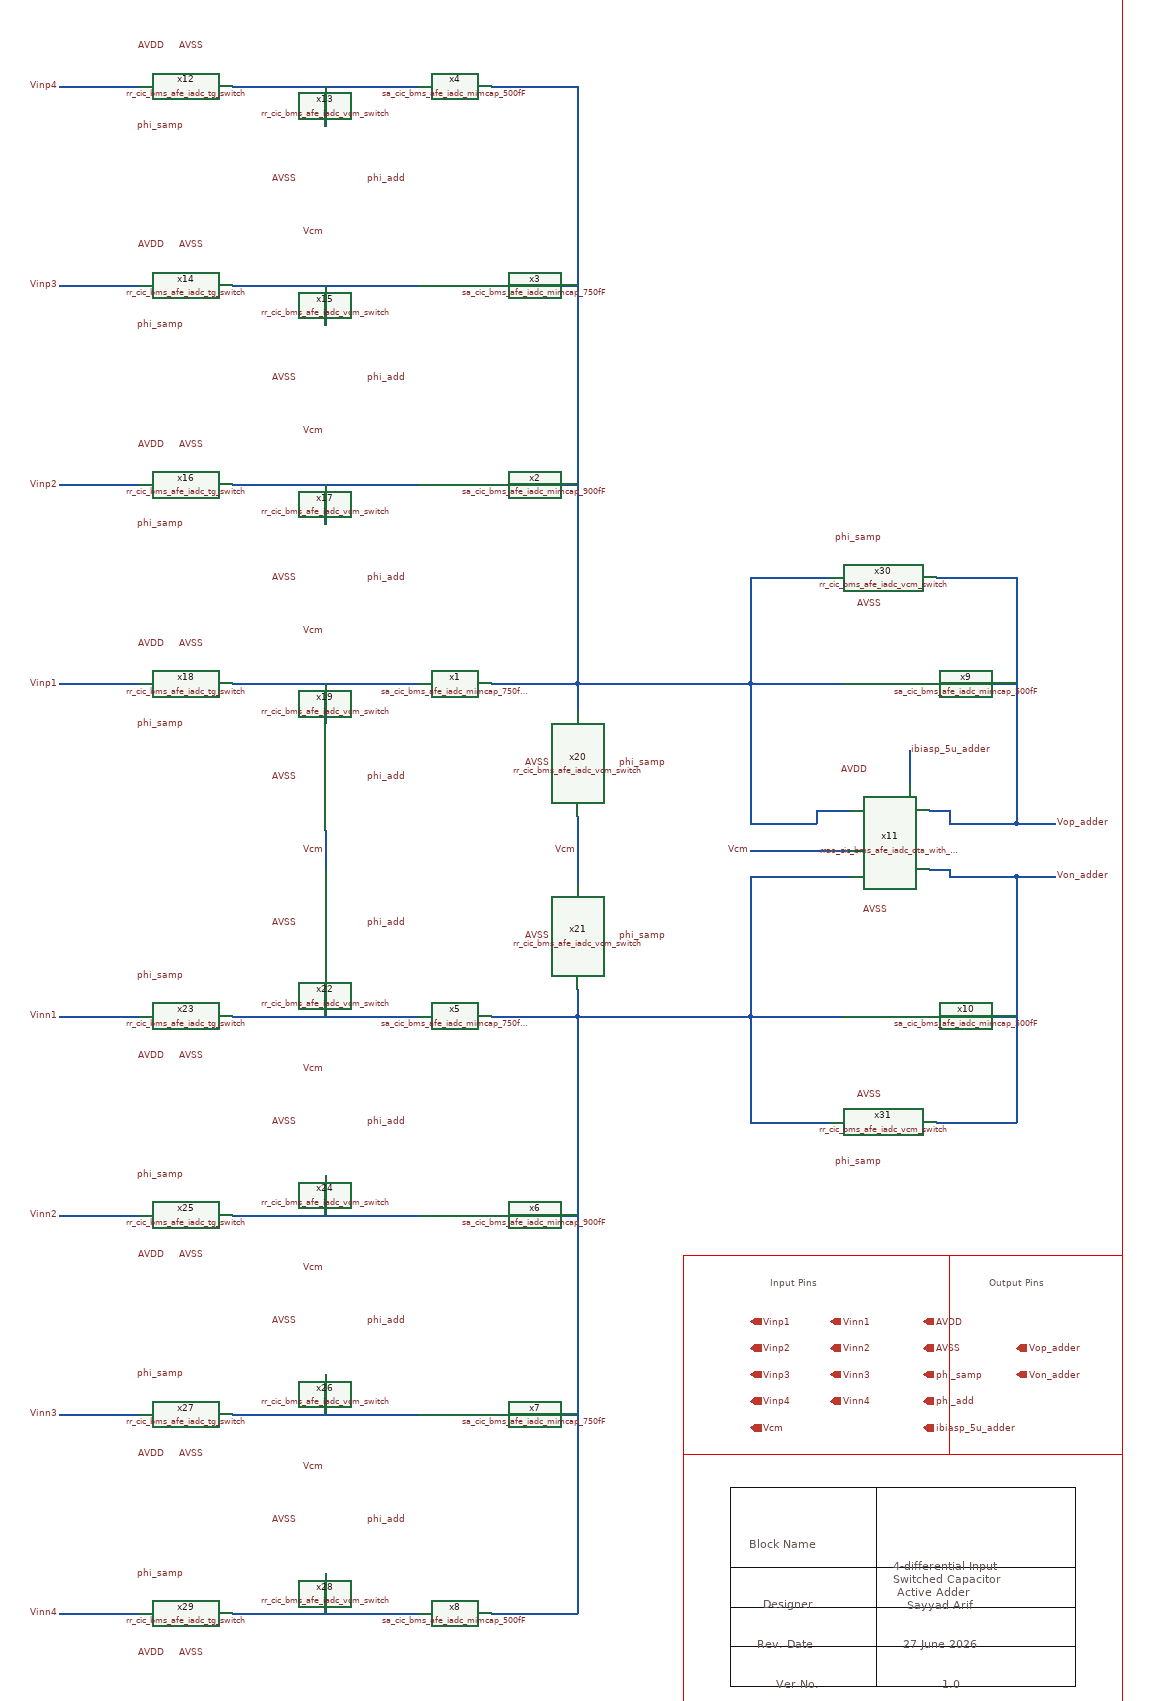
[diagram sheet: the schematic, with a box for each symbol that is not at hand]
v {xschem version=3.4.8RC file_version=1.3}
G {}
K {}
V {}
S {}
F {}
E {}
L 3 1130 -330 1130 -270 {}
L 3 1130 -270 1350 -270 {}
L 3 1350 -330 1350 -270 {}
L 3 1130 -330 1350 -330 {}
L 3 1350 -330 1350 -270 {}
L 3 1350 -270 1650 -270 {}
L 3 1650 -330 1650 -270 {}
L 3 1350 -330 1650 -330 {}
L 3 1130 -270 1130 -210 {}
L 3 1130 -210 1350 -210 {}
L 3 1350 -270 1350 -210 {}
L 3 1350 -270 1350 -210 {}
L 3 1350 -210 1650 -210 {}
L 3 1650 -270 1650 -210 {}
L 3 1130 -210 1130 -150 {}
L 3 1130 -150 1350 -150 {}
L 3 1350 -210 1350 -150 {}
L 3 1350 -210 1350 -150 {}
L 3 1350 -150 1650 -150 {}
L 3 1650 -210 1650 -150 {}
L 3 1130 -450 1130 -330 {}
L 3 1130 -330 1350 -330 {}
L 3 1350 -450 1350 -330 {}
L 3 1130 -450 1350 -450 {}
L 3 1350 -390 1350 -330 {}
L 3 1350 -330 1590 -330 {}
L 3 1650 -450 1650 -330 {}
L 3 1350 -450 1650 -450 {}
L 7 0 -100 1720 -100 {}
L 7 1720 -2720 1720 0 {}
L 7 0 0 1720 0 {}
L 7 0 -2720 0 0 {}
L 7 0 -2720 1720 -2720 {}
L 7 1060 -500 1720 -500 {}
L 7 1060 -800 1060 -500 {}
L 7 1060 -800 1460 -800 {}
L 7 1460 -800 1460 -500 {}
L 7 1460 -800 1720 -800 {}
L 7 1060 -500 1060 -100 {}
T {Input Pins} 1190 -770 0 0 0.4 0.4 {layer=7
weight=bold}
T {Output Pins} 1520 -770 0 0 0.4 0.4 {layer=7
weight=bold}
T {Designer} 1179 -286 2 1 0.5 0.5 {weight=bold layer=3}
T {Sayyad Arif} 1396 -284 2 1 0.5 0.5 {layer=3}
T {Rev. Date} 1170 -226 2 1 0.5 0.5 {weight=bold layer=3}
T {27 June 2026} 1390 -226 2 1 0.5 0.5 {layer=3}
T {Ver No.} 1200 -166 2 1 0.5 0.5 {weight=bold layer=3}
T {1.0} 1450 -166 2 1 0.5 0.5 {layer=3}
T {Block Name} 1159 -376 2 1 0.5 0.5 {weight=bold layer=3}
T {4-differential Input
Switched Capacitor
   Active Adder} 1376 -344 2 1 0.5 0.5 {layer=3}
N 520 -2560 520 -2500 {lab=#net1}
N 380 -2560 530 -2560 {lab=#net1}
N 530 -2560 660 -2560 {lab=#net1}
N 520 -2260 520 -2200 {lab=#net2}
N 520 -1960 520 -1900 {lab=#net3}
N 530 -1960 660 -1960 {lab=#net3}
N 520 -1660 520 -1600 {lab=#net4}
N 530 -1660 660 -1660 {lab=#net4}
N 120 -2560 240 -2560 {lab=Vinp4}
N 380 -2260 530 -2260 {lab=#net2}
N 120 -2260 240 -2260 {lab=Vinp3}
N 380 -1960 530 -1960 {lab=#net3}
N 120 -1960 240 -1960 {lab=Vinp2}
N 380 -1660 530 -1660 {lab=#net4}
N 120 -1660 240 -1660 {lab=Vinp1}
N 530 -2260 660 -2260 {lab=#net2}
N 900 -1660 900 -1620 {lab=#net5}
N 770 -1660 900 -1660 {lab=#net5}
N 900 -1460 900 -1360 {lab=Vcm}
N 520 -1220 520 -1160 {lab=#net6}
N 530 -1160 660 -1160 {lab=#net6}
N 380 -1160 530 -1160 {lab=#net6}
N 120 -1160 240 -1160 {lab=Vinn1}
N 520 -1440 520 -1380 {lab=Vcm}
N 770 -1160 900 -1160 {lab=#net7}
N 900 -1200 900 -1160 {lab=#net7}
N 520 -920 520 -860 {lab=#net8}
N 530 -860 660 -860 {lab=#net8}
N 380 -860 530 -860 {lab=#net8}
N 120 -860 240 -860 {lab=Vinn2}
N 520 -620 520 -560 {lab=#net9}
N 530 -560 660 -560 {lab=#net9}
N 380 -560 530 -560 {lab=#net9}
N 120 -560 240 -560 {lab=Vinn3}
N 520 -320 520 -260 {lab=#net10}
N 530 -260 660 -260 {lab=#net10}
N 380 -260 530 -260 {lab=#net10}
N 120 -260 240 -260 {lab=Vinn4}
N 770 -260 900 -260 {lab=#net7}
N 900 -1160 900 -260 {lab=#net7}
N 770 -860 900 -860 {lab=#net7}
N 770 -560 900 -560 {lab=#net7}
N 770 -1960 900 -1960 {lab=#net5}
N 770 -2260 900 -2260 {lab=#net5}
N 770 -2560 900 -2560 {lab=#net5}
N 900 -2560 900 -1660 {lab=#net5}
N 1400 -1560 1400 -1510 {lab=ibiasp_5u_adder}
N 1160 -1160 1300 -1160 {lab=#net7}
N 1160 -1370 1160 -1160 {lab=#net7}
N 1160 -1370 1260 -1370 {lab=#net7}
N 1160 -1660 1160 -1450 {lab=#net5}
N 1160 -1660 1300 -1660 {lab=#net5}
N 1160 -1820 1280 -1820 {lab=#net5}
N 1160 -1820 1160 -1660 {lab=#net5}
N 900 -1660 1160 -1660 {lab=#net5}
N 1460 -1450 1560 -1450 {lab=Vop_adder}
N 1560 -1820 1560 -1450 {lab=Vop_adder}
N 1440 -1820 1560 -1820 {lab=Vop_adder}
N 1410 -1660 1560 -1660 {lab=Vop_adder}
N 1160 -1000 1280 -1000 {lab=#net7}
N 1160 -1160 1160 -1000 {lab=#net7}
N 1560 -1370 1560 -1000 {lab=Von_adder}
N 1440 -1000 1560 -1000 {lab=Von_adder}
N 1460 -1370 1560 -1370 {lab=Von_adder}
N 1410 -1160 1560 -1160 {lab=Von_adder}
N 900 -1160 1160 -1160 {lab=#net7}
N 1160 -1410 1260 -1410 {lab=Vcm}
N 1560 -1450 1620 -1450 {lab=Vop_adder}
N 1560 -1370 1620 -1370 {lab=Von_adder}
N 1160 -1450 1260 -1450 {lab=#net5}
N 1260 -1470 1260 -1450 {lab=#net5}
N 1260 -1470 1310 -1470 {lab=#net5}
N 1260 -1370 1310 -1370 {lab=#net7}
N 1260 -1410 1310 -1410 {lab=Vcm}
N 1430 -1470 1460 -1470 {lab=Vop_adder}
N 1460 -1470 1460 -1450 {lab=Vop_adder}
N 1430 -1380 1460 -1380 {lab=Von_adder}
N 1460 -1380 1460 -1370 {lab=Von_adder}
C {lab_pin.sym} 1160 -1410 2 1 {name=p1 sig_type=std_logic lab=Vcm}
C {ipin.sym} 1160 -700 2 1 {name=p9 lab=Vinp1}
C {ipin.sym} 1280 -700 2 1 {name=p8 lab=Vinn1}
C {ipin.sym} 1160 -660 2 1 {name=p13 lab=Vinp2}
C {ipin.sym} 1280 -660 2 1 {name=p17 lab=Vinn2}
C {ipin.sym} 1160 -620 2 1 {name=p23 lab=Vinp3}
C {lab_pin.sym} 310 -2500 1 1 {name=p24 sig_type=std_logic lab=phi_samp}
C {lab_pin.sym} 520 -2340 3 0 {name=p25 sig_type=std_logic lab=Vcm}
C {ipin.sym} 1160 -580 2 1 {name=p27 lab=Vinp4}
C {ipin.sym} 1280 -620 2 1 {name=p29 lab=Vinn3}
C {ipin.sym} 1280 -580 2 1 {name=p33 lab=Vinn4}
C {opin.sym} 1560 -660 0 0 {name=p36 lab=Vop_adder}
C {opin.sym} 1560 -620 0 0 {name=p37 lab=Von_adder}
C {ipin.sym} 1160 -540 2 1 {name=p38 lab=Vcm}
C {ipin.sym} 1420 -620 2 1 {name=p39 lab=phi_samp}
C {ipin.sym} 1420 -580 2 1 {name=p40 lab=phi_add}
C {lab_pin.sym} 340 -2620 1 0 {name=p14 sig_type=std_logic lab=AVSS}
C {lab_pin.sym} 580 -2420 2 0 {name=p56 sig_type=std_logic lab=phi_add}
C {lab_pin.sym} 480 -2420 0 0 {name=p57 sig_type=std_logic lab=AVSS}
C {lab_pin.sym} 960 -1540 2 0 {name=p58 sig_type=std_logic lab=phi_samp}
C {lab_pin.sym} 1360 -1880 1 0 {name=p3 sig_type=std_logic lab=phi_samp}
C {ipin.sym} 1420 -700 2 1 {name=p4 lab=AVDD}
C {ipin.sym} 1420 -660 2 1 {name=p65 lab=AVSS}
C {dsm/Adder/sa_cic_bms_afe_iadc_mimcap_900fF.sym} 720 -1960 0 0 {name=x2}
C {dsm/Adder/sa_cic_bms_afe_iadc_mimcap_750fF.sym} 710 -2260 2 0 {name=x3}
C {dsm/Adder/sa_cic_bms_afe_iadc_mimcap_900fF.sym} 720 -860 2 1 {name=x6}
C {dsm/Adder/sa_cic_bms_afe_iadc_mimcap_750fF.sym} 710 -560 0 1 {name=x7}
C {dsm/Adder/sa_cic_bms_afe_iadc_mimcap_500fF.sym} 720 -260 2 1 {name=x8}
C {dsm/Adder/sa_cic_bms_afe_iadc_mimcap_500fF.sym} 1360 -1660 0 0 {name=x9}
C {dsm/Adder/sa_cic_bms_afe_iadc_mimcap_500fF.sym} 1360 -1160 2 1 {name=x10}
C {title.sym} 400 -50 0 0 {name=l1 author="Sayyad Arif"}
C {dsm/Adder/rr_cic_bms_afe_iadc_vcm_switch.sym} 520 -2420 1 1 {name=x13}
C {lab_pin.sym} 520 -2040 3 0 {name=p66 sig_type=std_logic lab=Vcm}
C {lab_pin.sym} 580 -2120 2 0 {name=p67 sig_type=std_logic lab=phi_add}
C {lab_pin.sym} 480 -2120 0 0 {name=p68 sig_type=std_logic lab=AVSS}
C {dsm/Adder/rr_cic_bms_afe_iadc_vcm_switch.sym} 520 -2120 1 1 {name=x15}
C {lab_pin.sym} 280 -2620 1 0 {name=p69 sig_type=std_logic lab=AVDD}
C {lab_pin.sym} 520 -1740 3 0 {name=p73 sig_type=std_logic lab=Vcm}
C {lab_pin.sym} 580 -1820 2 0 {name=p74 sig_type=std_logic lab=phi_add}
C {lab_pin.sym} 480 -1820 0 0 {name=p75 sig_type=std_logic lab=AVSS}
C {dsm/Adder/rr_cic_bms_afe_iadc_vcm_switch.sym} 520 -1820 1 1 {name=x17}
C {lab_pin.sym} 580 -1520 2 0 {name=p80 sig_type=std_logic lab=phi_add}
C {lab_pin.sym} 480 -1520 0 0 {name=p81 sig_type=std_logic lab=AVSS}
C {dsm/Adder/rr_cic_bms_afe_iadc_vcm_switch.sym} 520 -1520 1 1 {name=x19}
C {dsm/Adder/rr_cic_bms_afe_iadc_tg_switch.sym} 310 -2560 0 0 {name=x12}
C {lab_pin.sym} 120 -2560 0 0 {name=p2 sig_type=std_logic lab=Vinp4}
C {lab_pin.sym} 310 -2200 1 1 {name=p7 sig_type=std_logic lab=phi_samp}
C {lab_pin.sym} 340 -2320 1 0 {name=p10 sig_type=std_logic lab=AVSS}
C {lab_pin.sym} 280 -2320 1 0 {name=p11 sig_type=std_logic lab=AVDD}
C {dsm/Adder/rr_cic_bms_afe_iadc_tg_switch.sym} 310 -2260 0 0 {name=x14}
C {lab_pin.sym} 120 -2260 0 0 {name=p12 sig_type=std_logic lab=Vinp3}
C {lab_pin.sym} 310 -1900 1 1 {name=p20 sig_type=std_logic lab=phi_samp}
C {lab_pin.sym} 340 -2020 1 0 {name=p21 sig_type=std_logic lab=AVSS}
C {lab_pin.sym} 280 -2020 1 0 {name=p22 sig_type=std_logic lab=AVDD}
C {dsm/Adder/rr_cic_bms_afe_iadc_tg_switch.sym} 310 -1960 0 0 {name=x16}
C {lab_pin.sym} 120 -1960 0 0 {name=p26 sig_type=std_logic lab=Vinp2}
C {lab_pin.sym} 310 -1600 1 1 {name=p41 sig_type=std_logic lab=phi_samp}
C {lab_pin.sym} 340 -1720 1 0 {name=p42 sig_type=std_logic lab=AVSS}
C {lab_pin.sym} 280 -1720 1 0 {name=p44 sig_type=std_logic lab=AVDD}
C {dsm/Adder/rr_cic_bms_afe_iadc_tg_switch.sym} 310 -1660 0 0 {name=x18}
C {lab_pin.sym} 120 -1660 0 0 {name=p45 sig_type=std_logic lab=Vinp1}
C {lab_pin.sym} 900 -1410 0 0 {name=p46 sig_type=std_logic lab=Vcm}
C {lab_pin.sym} 860 -1540 0 0 {name=p47 sig_type=std_logic lab=AVSS}
C {dsm/Adder/rr_cic_bms_afe_iadc_vcm_switch.sym} 900 -1540 1 1 {name=x20}
C {lab_pin.sym} 860 -1280 2 1 {name=p70 sig_type=std_logic lab=AVSS}
C {dsm/Adder/rr_cic_bms_afe_iadc_vcm_switch.sym} 900 -1280 1 0 {name=x21}
C {lab_pin.sym} 960 -1280 2 0 {name=p71 sig_type=std_logic lab=phi_samp}
C {lab_pin.sym} 520 -1410 2 1 {name=p43 sig_type=std_logic lab=Vcm}
C {lab_pin.sym} 580 -1300 0 1 {name=p59 sig_type=std_logic lab=phi_add}
C {lab_pin.sym} 480 -1300 2 1 {name=p60 sig_type=std_logic lab=AVSS}
C {dsm/Adder/rr_cic_bms_afe_iadc_vcm_switch.sym} 520 -1300 1 0 {name=x22}
C {lab_pin.sym} 310 -1220 1 0 {name=p61 sig_type=std_logic lab=phi_samp}
C {lab_pin.sym} 340 -1100 1 1 {name=p72 sig_type=std_logic lab=AVSS}
C {lab_pin.sym} 280 -1100 1 1 {name=p76 sig_type=std_logic lab=AVDD}
C {dsm/Adder/rr_cic_bms_afe_iadc_tg_switch.sym} 310 -1160 2 1 {name=x23}
C {lab_pin.sym} 120 -1160 2 1 {name=p77 sig_type=std_logic lab=Vinn1}
C {lab_pin.sym} 580 -1000 0 1 {name=p78 sig_type=std_logic lab=phi_add}
C {lab_pin.sym} 480 -1000 2 1 {name=p79 sig_type=std_logic lab=AVSS}
C {dsm/Adder/rr_cic_bms_afe_iadc_vcm_switch.sym} 520 -1000 1 0 {name=x24}
C {lab_pin.sym} 310 -920 1 0 {name=p82 sig_type=std_logic lab=phi_samp}
C {lab_pin.sym} 340 -800 1 1 {name=p83 sig_type=std_logic lab=AVSS}
C {lab_pin.sym} 280 -800 1 1 {name=p84 sig_type=std_logic lab=AVDD}
C {dsm/Adder/rr_cic_bms_afe_iadc_tg_switch.sym} 310 -860 2 1 {name=x25}
C {lab_pin.sym} 120 -860 2 1 {name=p85 sig_type=std_logic lab=Vinn2}
C {lab_pin.sym} 520 -1080 3 1 {name=p86 sig_type=std_logic lab=Vcm}
C {lab_pin.sym} 580 -700 0 1 {name=p87 sig_type=std_logic lab=phi_add}
C {lab_pin.sym} 480 -700 2 1 {name=p88 sig_type=std_logic lab=AVSS}
C {dsm/Adder/rr_cic_bms_afe_iadc_vcm_switch.sym} 520 -700 1 0 {name=x26}
C {lab_pin.sym} 310 -620 1 0 {name=p89 sig_type=std_logic lab=phi_samp}
C {lab_pin.sym} 340 -500 1 1 {name=p90 sig_type=std_logic lab=AVSS}
C {lab_pin.sym} 280 -500 1 1 {name=p91 sig_type=std_logic lab=AVDD}
C {dsm/Adder/rr_cic_bms_afe_iadc_tg_switch.sym} 310 -560 2 1 {name=x27}
C {lab_pin.sym} 120 -560 2 1 {name=p92 sig_type=std_logic lab=Vinn3}
C {lab_pin.sym} 520 -780 3 1 {name=p93 sig_type=std_logic lab=Vcm}
C {lab_pin.sym} 580 -400 0 1 {name=p94 sig_type=std_logic lab=phi_add}
C {lab_pin.sym} 480 -400 2 1 {name=p95 sig_type=std_logic lab=AVSS}
C {dsm/Adder/rr_cic_bms_afe_iadc_vcm_switch.sym} 520 -400 1 0 {name=x28}
C {lab_pin.sym} 310 -320 1 0 {name=p96 sig_type=std_logic lab=phi_samp}
C {lab_pin.sym} 340 -200 1 1 {name=p97 sig_type=std_logic lab=AVSS}
C {lab_pin.sym} 280 -200 1 1 {name=p98 sig_type=std_logic lab=AVDD}
C {dsm/Adder/rr_cic_bms_afe_iadc_tg_switch.sym} 310 -260 2 1 {name=x29}
C {lab_pin.sym} 120 -260 2 1 {name=p99 sig_type=std_logic lab=Vinn4}
C {lab_pin.sym} 520 -480 3 1 {name=p100 sig_type=std_logic lab=Vcm}
C {lab_pin.sym} 1370 -1320 3 0 {name=p5 sig_type=std_logic lab=AVSS}
C {lab_pin.sym} 1340 -1530 1 0 {name=p6 sig_type=std_logic lab=AVDD}
C {lab_pin.sym} 1400 -1560 2 0 {name=p15 sig_type=std_logic lab=ibiasp_5u_adder}
C {dsm/Adder/rr_cic_bms_afe_iadc_vcm_switch.sym} 1360 -1820 0 0 {name=x30}
C {lab_pin.sym} 1360 -1780 3 0 {name=p16 sig_type=std_logic lab=AVSS}
C {lab_pin.sym} 1360 -940 1 1 {name=p18 sig_type=std_logic lab=phi_samp}
C {dsm/Adder/rr_cic_bms_afe_iadc_vcm_switch.sym} 1360 -1000 2 1 {name=x31}
C {lab_pin.sym} 1360 -1040 3 1 {name=p19 sig_type=std_logic lab=AVSS}
C {lab_pin.sym} 1620 -1450 2 0 {name=p28 sig_type=std_logic lab=Vop_adder}
C {lab_pin.sym} 1620 -1370 2 0 {name=p30 sig_type=std_logic lab=Von_adder}
C {ipin.sym} 1420 -540 2 1 {name=p31 lab=ibiasp_5u_adder}
C {Design/rrao_cic_bms_afe_iadc_ota_with_cmfb.sym} 1360 -1410 0 0 {name=x11}
C {dsm/Adder/sa_cic_bms_afe_iadc_mimcap_500fF.sym} 720 -2560 2 1 {name=x4}
C {dsm/Adder/sa_cic_bms_afe_iadc_mimcap_750fF_v2.sym} 720 -1660 0 0 {name=x1}
C {dsm/Adder/sa_cic_bms_afe_iadc_mimcap_750fF_v2.sym} 720 -1160 0 0 {name=x5}
